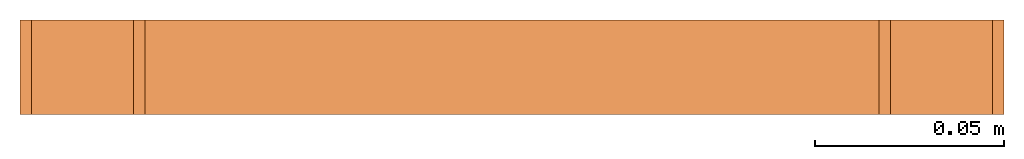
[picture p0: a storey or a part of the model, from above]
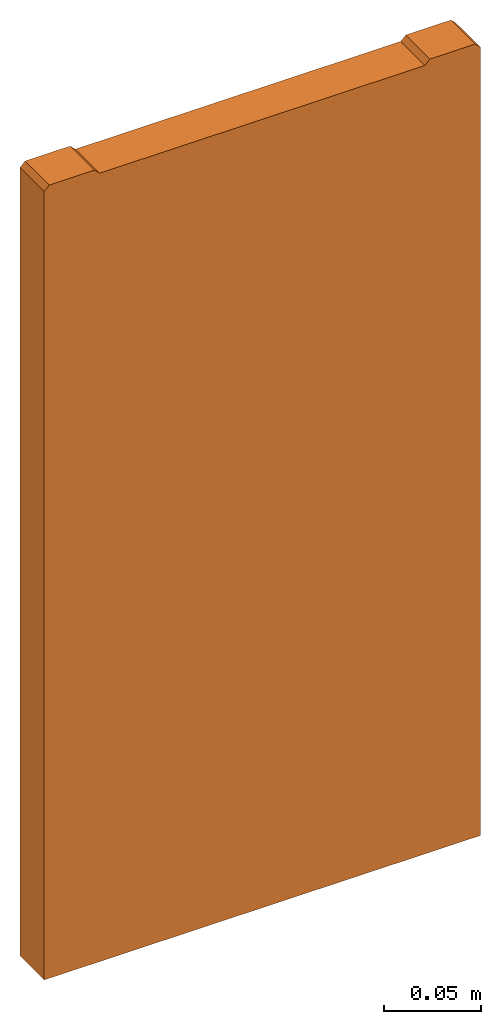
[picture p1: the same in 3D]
Properties of the parts of a building model (IFC2X3)

# File
Description: ViewDefinition [CoordinationView]
File name: 33306 - PD200 F 306 Closing endcap.ifc
Time: 2013-10-11T12:58:44
Written by: Autodesk Revit 2013
Made in: 20120221_2030(x64)

# IfcProject, Project Number
LongName: Project Name; Phase: Project Status

# IfcSite, Default
RefLatitude: 42, 21, 30, 344238; RefLongitude: -71, -3, -35, -194702; RefElevation: 0 mm

# IfcBuilding
Pset_BuildingCommon - NumberOfStoreys: 2
Other - Project Status: Project Status; Project Address: Enter address here; Project Issue Date: Issue Date; Client Name: Owner; Project Name: Project Name; Project Number: Project Number

# IfcBuildingStorey (2)
Graphics - Line Pattern: Center; Symbol at End 2 Default: yes; Symbol: M_Level Head - Circle: M_Level Head - Circle; Color: 0; Symbol at End 1 Default: no; Line Weight: 1
Constraints - Elevation Base: 0
Dimensions - Computation Height: 0 mm
Identity Data - Structural: no; Building Story: yes
Name | LongName = Name | Elevation (mm) = Constraints, Elevation (mm)
B.O. Footing | B.O. Footing | -4600
T.O. Footing | T.O. Footing | -4300

# IfcBuildingElementProxy: 33306 - PD200 F 306 Closing endcap, Civil-Drainage-Channel-ACO-RoadDrain 200:33306 - PD200 F 306 Closing endcap:33306 - PD200 F 306 Closing endcap:309971
In: B.O. Footing
Material: Acetal Resin, Black
Other - CreatedBy: www.aco.co.uk; Revision: 1
Construction - Channel 260mm Wide: no; Inlet Outlet end cap: no; Closing End Cap: yes; Access unit: no
Constraints - Moves With Nearby Elements: no; Level: Level: T.O. Footing
Dimensions - Length: 500 mm; Custom Void Length: 0 mm; Straight Void Length: 25 mm; Volume: 3235000 mm3; Void Depth: -500 mm; Total Depth: 500 mm; Pipe Depth: 3000 mm; I/O End Cap Void: 3650 mm; Invert Depth.: 275 mm; Straight Void Start: 0 mm
Phasing - Phase Created: Phase 1
Pset_BuildingElementProxyCommon - Reference: 33306 - PD200 F 306 Closing endcap
Data - Concrete Surround Volume - Load Class F 900 - Concrete Pavement: N/A; Product Dimensions: 25mm x 260mm x 500mm (LxWxH); Connection Pipe O.D: N/A; Channel C.S.A: N/A; ACO Hydraulic Design Software: N/A; Load Class: N/A; Product Standard: N/A; Hydraulic Performance: N/A; Installation - Concrete Grade: N/A; Invert Depth: N/A; Product Weight: 4.6 Kg
Green Building Properties - Channel Recycled Material Content: N/A; Channel Recyclable: N/A; End Cap Recycled Material Content: 20% minimum; Access Cover/Frame Recycled Material Content: N/A; End Cap Recyclable: Fully recyclable; Access Cover/Frame Recyclable: N/A
Materials and Finishes - Grating Finish: N/A; Grating Colour: N/A; Access Cover/Frame Colour: N/A; Connection Pipe Colour: N/A; End Cap Colour: Black; Connection Pipe Material: N/A; Grating Material: N/A; End Cap Material: Vienite® Synthetic Resin Concrete; Channel Material: N/A; Access Cover/Frame Finish: N/A; Channel Colour: N/A; Access Cover/Frame Material: N/A
General - SerialNumber: 0.000000; TagNumber: 0.000000
Identity Data - Installation guidelines: http://www.aco.co.uk/download.php?id=256; Telephone: +44 (0)1462 816666; Price: POA - contact ACO; Address: ACO Business Park, Hitchin Road, Shefford, Bedfordshire, United Kingdom SG17 5TE; URL: www.aco.co.uk; e-mail Technical: technical@aco.co.uk; Product brochure: http://www.aco.co.uk/download.php?id=256; Product Code: 33306; Watermark 2: This file is water marked and users are prohibited to reproduce, adapt, distribute this information; Type Comments: ACO RoadDrain PD200 F 306 Closing End Cap; OmniClass Title: Rainwater Removal; Watermark 1: This file is the property of ACO Technologies PLC; Product Page URL: http://www.aco.co.uk/product_detail.php?id=21; Manufacturer: ACO Technologies plc - ACO Water Management Division; Assembly Code: D2040; Model: ACO RoadDrain 200 PD200F; Model Description: Monolithic Channel drainage system; e-mail Sales: customersupport@aco.co.uk; OmniClass Number: 23.70.50.24; Watermarked By: www.aco.co.uk; Fax: +44 (0)1462 815895; Cost: 0; Maintenance guidelines: http://www.aco.co.uk/download.php?id=256; Watermarked With: BIM Manager Premium Suite; Assembly Description: Rain Water Drainage

# IfcOpeningElement: Recess (2)
In: T.O. Footing
Constraints - Room Bounding: yes; Related to Mass: no; Height Offset From Level: 0 mm; Level: Level: T.O. Footing
Dimensions - Area: 26010000 mm2; Thickness: 1550 mm; Volume: 40312250000 mm3; Perimeter: 20400 mm
Structural - Structural: no; Enable Analytical Model: no
Phasing - Phase Created: Phase 1
Analytical Properties - Thermal Resistance (R): 1.79211; Heat Transfer Coefficient (U): 0.558; Roughness: 1; Thermal mass: 2039700; Absorptance: 0.1
Construction - Function: 0; Default Thickness: 1550 mm
Graphics - Coarse Scale Fill Color: 0
Materials and Finishes - Structural Material: Grass

# IfcSlab: Floor:Generic Floor - 400mm, Floor:Generic Floor - 400mm:136436
In: T.O. Footing
PredefinedType: FLOOR; Material: Grass 50 mm, Earth 1500 mm
Constraints - Room Bounding: yes; Related to Mass: no; Height Offset From Level: 0 mm; Level: Level: T.O. Footing
Dimensions - Area: 26010000 mm2; Thickness: 1550 mm; Volume: 40312250000 mm3; Perimeter: 20400 mm
Structural - Structural: no; Enable Analytical Model: no
Phasing - Phase Created: Phase 1
Pset_SlabCommon - Reference: Generic Floor - 400mm; IsExternal: no; LoadBearing: yes
Analytical Properties - Thermal Resistance (R): 1.79211; Heat Transfer Coefficient (U): 0.558; Roughness: 1; Thermal mass: 2039700; Absorptance: 0.1
Construction - Function: 0; Default Thickness: 1550 mm
Graphics - Coarse Scale Fill Color: 0
Materials and Finishes - Structural Material: Grass
